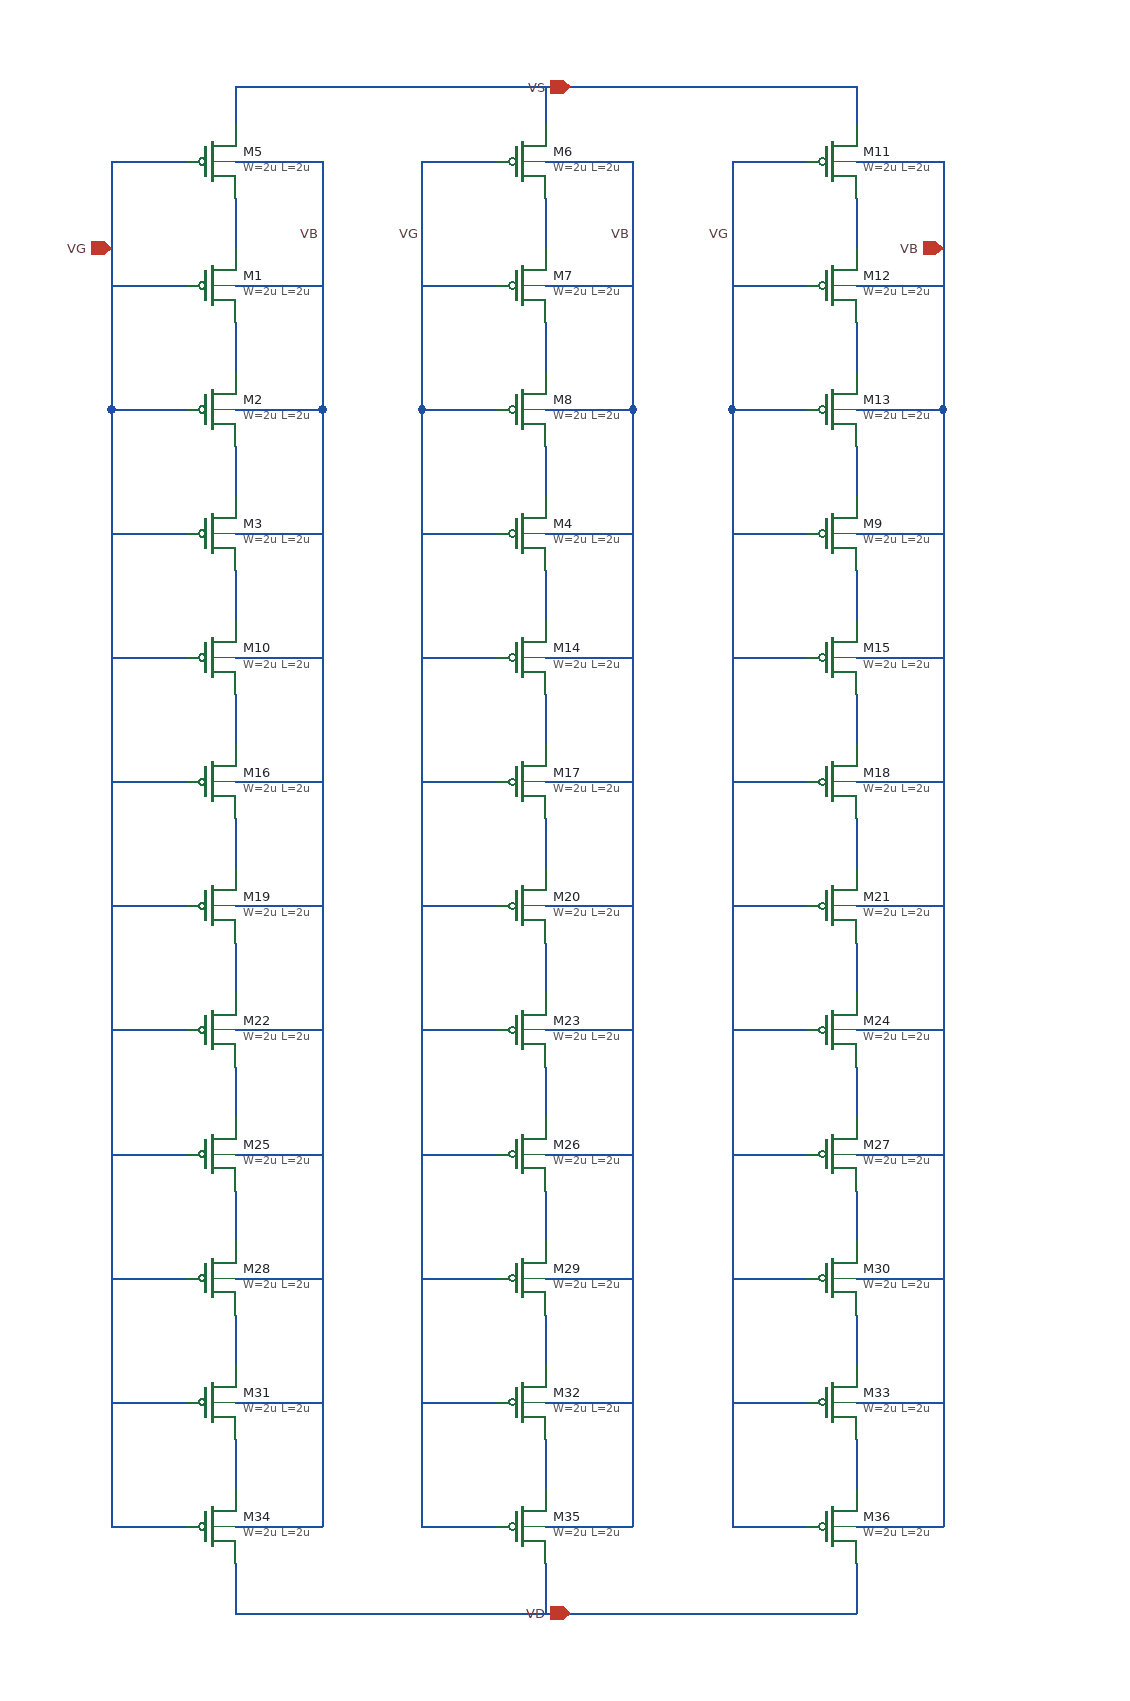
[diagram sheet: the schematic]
v {xschem version=3.4.5 file_version=1.2
}
G {}
K {}
V {}
S {}
E {}
N 10 -60 10 -30 {
lab=VS}
N 10 30 10 70 {
lab=#net1}
N 10 0 80 0 {
lab=VB}
N -90 0 -30 0 {
lab=VG}
N 10 130 10 170 {
lab=#net2}
N 10 1130 10 1170 {
lab=VD}
N -90 200 -30 200 {
lab=VG}
N -90 100 -30 100 {
lab=VG}
N 10 200 80 200 {
lab=VB}
N 10 100 80 100 {
lab=VB}
N 260 -60 260 -30 {
lab=VS}
N 260 30 260 70 {
lab=#net3}
N 260 0 330 0 {
lab=VB}
N 160 0 220 0 {
lab=VG}
N 260 130 260 170 {
lab=#net4}
N 260 1130 260 1170 {
lab=VD}
N 160 200 220 200 {
lab=VG}
N 160 100 220 100 {
lab=VG}
N 260 200 330 200 {
lab=VB}
N 260 100 330 100 {
lab=VB}
N 510 -60 510 -30 {
lab=VS}
N 510 30 510 70 {
lab=#net5}
N 510 0 580 0 {
lab=VB}
N 410 0 470 0 {
lab=#net6}
N 510 130 510 170 {
lab=#net7}
N 510 1130 510 1170 {
lab=VD}
N 410 200 470 200 {
lab=#net6}
N 410 100 470 100 {
lab=#net6}
N 510 200 580 200 {
lab=VB}
N 510 100 580 100 {
lab=VB}
N 10 -60 510 -60 {
lab=VS}
N 10 1170 510 1170 {
lab=VD}
N -90 0 -90 200 {
lab=VG}
N 80 -0 80 200 {
lab=VB}
N 160 -0 160 190 {
lab=VG}
N 160 190 160 200 {
lab=VG}
N 330 0 330 200 {
lab=VB}
N 410 -0 410 200 {
lab=#net6}
N 580 0 580 200 {
lab=VB}
N 10 230 10 270 {
lab=#net2}
N 10 300 80 300 {
lab=VB}
N 260 230 260 270 {
lab=#net4}
N 160 300 220 300 {
lab=VG}
N 260 300 330 300 {
lab=VB}
N 510 230 510 270 {
lab=#net7}
N 410 300 470 300 {
lab=#net6}
N 10 330 10 370 {
lab=#net2}
N 10 400 80 400 {
lab=VB}
N 260 330 260 370 {
lab=#net4}
N 160 400 220 400 {
lab=VG}
N 260 400 330 400 {
lab=VB}
N 510 330 510 370 {
lab=#net7}
N 410 400 470 400 {
lab=#net6}
N 10 430 10 470 {
lab=#net2}
N 10 500 80 500 {
lab=VB}
N 260 430 260 470 {
lab=#net4}
N 160 500 220 500 {
lab=VG}
N 260 500 330 500 {
lab=VB}
N 510 430 510 470 {
lab=#net7}
N 410 500 470 500 {
lab=#net6}
N 10 530 10 570 {
lab=#net2}
N 10 600 80 600 {
lab=VB}
N 260 530 260 570 {
lab=#net4}
N 160 600 220 600 {
lab=VG}
N 260 600 330 600 {
lab=VB}
N 510 530 510 570 {
lab=#net7}
N 410 600 470 600 {
lab=#net6}
N 10 630 10 670 {
lab=#net2}
N 10 700 80 700 {
lab=VB}
N 260 630 260 670 {
lab=#net4}
N 160 700 220 700 {
lab=VG}
N 260 700 330 700 {
lab=VB}
N 510 630 510 670 {
lab=#net7}
N 410 700 470 700 {
lab=#net6}
N 10 730 10 770 {
lab=#net2}
N 10 800 80 800 {
lab=VB}
N 260 730 260 770 {
lab=#net4}
N 160 800 220 800 {
lab=VG}
N 260 800 330 800 {
lab=VB}
N 510 730 510 770 {
lab=#net7}
N 410 800 470 800 {
lab=#net6}
N 10 830 10 870 {
lab=#net2}
N 10 900 80 900 {
lab=VB}
N 260 830 260 870 {
lab=#net4}
N 160 900 220 900 {
lab=VG}
N 260 900 330 900 {
lab=VB}
N 510 830 510 870 {
lab=#net7}
N 410 900 470 900 {
lab=#net6}
N 10 930 10 970 {
lab=#net2}
N 10 1000 80 1000 {
lab=VB}
N 260 930 260 970 {
lab=#net4}
N 160 1000 220 1000 {
lab=VG}
N 260 1000 330 1000 {
lab=VB}
N 510 930 510 970 {
lab=#net7}
N 410 1000 470 1000 {
lab=#net6}
N 10 1030 10 1070 {
lab=#net2}
N 10 1100 80 1100 {
lab=VB}
N 260 1030 260 1070 {
lab=#net4}
N 160 1100 220 1100 {
lab=VG}
N 260 1100 330 1100 {
lab=VB}
N 510 1030 510 1070 {
lab=#net7}
N 410 1100 470 1100 {
lab=#net6}
N 160 1090 160 1100 {
lab=VG}
N 160 200 160 1090 {}
N 330 200 330 1100 {}
N 410 200 410 1100 {}
N 580 200 580 1100 {}
N 510 1100 580 1100 {}
N 510 1000 580 1000 {}
N 510 900 580 900 {}
N 510 800 580 800 {}
N 510 700 570 700 {}
N 570 700 580 700 {}
N 510 600 580 600 {}
N 510 500 580 500 {}
N 510 400 580 400 {}
N 510 300 580 300 {}
N 80 200 80 1100 {}
N -90 200 -90 1100 {}
N -90 1100 -30 1100 {}
N -90 1000 -30 1000 {}
N -90 900 -30 900 {}
N -90 800 -30 800 {}
N -90 700 -30 700 {}
N -90 600 -30 600 {}
N -90 500 -30 500 {}
N -90 400 -30 400 {}
N -90 300 -30 300 {}
C {devices/iopin.sym} 580 70 0 0 {name=p2 lab=VB}
C {devices/iopin.sym} -90 70 2 0 {name=p3 lab=VG}
C {symbols/pfet_03v3.sym} -10 0 0 0 {name=M5
L=2u
W=2u
nf=1
m=1
ad="'int((nf+1)/2) * W/nf * 0.18u'"
pd="'2*int((nf+1)/2) * (W/nf + 0.18u)'"
as="'int((nf+2)/2) * W/nf * 0.18u'"
ps="'2*int((nf+2)/2) * (W/nf + 0.18u)'"
nrd="'0.18u / W'" nrs="'0.18u / W'"
sa=0 sb=0 sd=0
model=pfet_03v3
spiceprefix=X
}
C {devices/iopin.sym} 280 -60 3 0 {name=p4 lab=VS}
C {devices/iopin.sym} 280 1170 1 0 {name=p1 lab=VD}
C {symbols/pfet_03v3.sym} -10 100 0 0 {name=M1
L=2u
W=2u
nf=1
m=1
ad="'int((nf+1)/2) * W/nf * 0.18u'"
pd="'2*int((nf+1)/2) * (W/nf + 0.18u)'"
as="'int((nf+2)/2) * W/nf * 0.18u'"
ps="'2*int((nf+2)/2) * (W/nf + 0.18u)'"
nrd="'0.18u / W'" nrs="'0.18u / W'"
sa=0 sb=0 sd=0
model=pfet_03v3
spiceprefix=X
}
C {symbols/pfet_03v3.sym} -10 200 0 0 {name=M2
L=2u
W=2u
nf=1
m=1
ad="'int((nf+1)/2) * W/nf * 0.18u'"
pd="'2*int((nf+1)/2) * (W/nf + 0.18u)'"
as="'int((nf+2)/2) * W/nf * 0.18u'"
ps="'2*int((nf+2)/2) * (W/nf + 0.18u)'"
nrd="'0.18u / W'" nrs="'0.18u / W'"
sa=0 sb=0 sd=0
model=pfet_03v3
spiceprefix=X
}
C {symbols/pfet_03v3.sym} 240 0 0 0 {name=M6
L=2u
W=2u
nf=1
m=1
ad="'int((nf+1)/2) * W/nf * 0.18u'"
pd="'2*int((nf+1)/2) * (W/nf + 0.18u)'"
as="'int((nf+2)/2) * W/nf * 0.18u'"
ps="'2*int((nf+2)/2) * (W/nf + 0.18u)'"
nrd="'0.18u / W'" nrs="'0.18u / W'"
sa=0 sb=0 sd=0
model=pfet_03v3
spiceprefix=X
}
C {symbols/pfet_03v3.sym} 240 100 0 0 {name=M7
L=2u
W=2u
nf=1
m=1
ad="'int((nf+1)/2) * W/nf * 0.18u'"
pd="'2*int((nf+1)/2) * (W/nf + 0.18u)'"
as="'int((nf+2)/2) * W/nf * 0.18u'"
ps="'2*int((nf+2)/2) * (W/nf + 0.18u)'"
nrd="'0.18u / W'" nrs="'0.18u / W'"
sa=0 sb=0 sd=0
model=pfet_03v3
spiceprefix=X
}
C {symbols/pfet_03v3.sym} 240 200 0 0 {name=M8
L=2u
W=2u
nf=1
m=1
ad="'int((nf+1)/2) * W/nf * 0.18u'"
pd="'2*int((nf+1)/2) * (W/nf + 0.18u)'"
as="'int((nf+2)/2) * W/nf * 0.18u'"
ps="'2*int((nf+2)/2) * (W/nf + 0.18u)'"
nrd="'0.18u / W'" nrs="'0.18u / W'"
sa=0 sb=0 sd=0
model=pfet_03v3
spiceprefix=X
}
C {symbols/pfet_03v3.sym} 490 0 0 0 {name=M11
L=2u
W=2u
nf=1
m=1
ad="'int((nf+1)/2) * W/nf * 0.18u'"
pd="'2*int((nf+1)/2) * (W/nf + 0.18u)'"
as="'int((nf+2)/2) * W/nf * 0.18u'"
ps="'2*int((nf+2)/2) * (W/nf + 0.18u)'"
nrd="'0.18u / W'" nrs="'0.18u / W'"
sa=0 sb=0 sd=0
model=pfet_03v3
spiceprefix=X
}
C {symbols/pfet_03v3.sym} 490 100 0 0 {name=M12
L=2u
W=2u
nf=1
m=1
ad="'int((nf+1)/2) * W/nf * 0.18u'"
pd="'2*int((nf+1)/2) * (W/nf + 0.18u)'"
as="'int((nf+2)/2) * W/nf * 0.18u'"
ps="'2*int((nf+2)/2) * (W/nf + 0.18u)'"
nrd="'0.18u / W'" nrs="'0.18u / W'"
sa=0 sb=0 sd=0
model=pfet_03v3
spiceprefix=X
}
C {symbols/pfet_03v3.sym} 490 200 0 0 {name=M13
L=2u
W=2u
nf=1
m=1
ad="'int((nf+1)/2) * W/nf * 0.18u'"
pd="'2*int((nf+1)/2) * (W/nf + 0.18u)'"
as="'int((nf+2)/2) * W/nf * 0.18u'"
ps="'2*int((nf+2)/2) * (W/nf + 0.18u)'"
nrd="'0.18u / W'" nrs="'0.18u / W'"
sa=0 sb=0 sd=0
model=pfet_03v3
spiceprefix=X
}
C {devices/lab_wire.sym} 80 60 0 0 {name=p9 sig_type=std_logic lab=VB}
C {devices/lab_wire.sym} 330 60 0 0 {name=p5 sig_type=std_logic lab=VB}
C {devices/lab_wire.sym} 160 60 0 0 {name=p6 sig_type=std_logic lab=VG
}
C {devices/lab_wire.sym} 410 60 0 0 {name=p7 sig_type=std_logic lab=VG
}
C {symbols/pfet_03v3.sym} -10 300 0 0 {name=M3
L=2u
W=2u
nf=1
m=1
ad="'int((nf+1)/2) * W/nf * 0.18u'"
pd="'2*int((nf+1)/2) * (W/nf + 0.18u)'"
as="'int((nf+2)/2) * W/nf * 0.18u'"
ps="'2*int((nf+2)/2) * (W/nf + 0.18u)'"
nrd="'0.18u / W'" nrs="'0.18u / W'"
sa=0 sb=0 sd=0
model=pfet_03v3
spiceprefix=X
}
C {symbols/pfet_03v3.sym} 240 300 0 0 {name=M4
L=2u
W=2u
nf=1
m=1
ad="'int((nf+1)/2) * W/nf * 0.18u'"
pd="'2*int((nf+1)/2) * (W/nf + 0.18u)'"
as="'int((nf+2)/2) * W/nf * 0.18u'"
ps="'2*int((nf+2)/2) * (W/nf + 0.18u)'"
nrd="'0.18u / W'" nrs="'0.18u / W'"
sa=0 sb=0 sd=0
model=pfet_03v3
spiceprefix=X
}
C {symbols/pfet_03v3.sym} 490 300 0 0 {name=M9
L=2u
W=2u
nf=1
m=1
ad="'int((nf+1)/2) * W/nf * 0.18u'"
pd="'2*int((nf+1)/2) * (W/nf + 0.18u)'"
as="'int((nf+2)/2) * W/nf * 0.18u'"
ps="'2*int((nf+2)/2) * (W/nf + 0.18u)'"
nrd="'0.18u / W'" nrs="'0.18u / W'"
sa=0 sb=0 sd=0
model=pfet_03v3
spiceprefix=X
}
C {symbols/pfet_03v3.sym} -10 400 0 0 {name=M10
L=2u
W=2u
nf=1
m=1
ad="'int((nf+1)/2) * W/nf * 0.18u'"
pd="'2*int((nf+1)/2) * (W/nf + 0.18u)'"
as="'int((nf+2)/2) * W/nf * 0.18u'"
ps="'2*int((nf+2)/2) * (W/nf + 0.18u)'"
nrd="'0.18u / W'" nrs="'0.18u / W'"
sa=0 sb=0 sd=0
model=pfet_03v3
spiceprefix=X
}
C {symbols/pfet_03v3.sym} 240 400 0 0 {name=M14
L=2u
W=2u
nf=1
m=1
ad="'int((nf+1)/2) * W/nf * 0.18u'"
pd="'2*int((nf+1)/2) * (W/nf + 0.18u)'"
as="'int((nf+2)/2) * W/nf * 0.18u'"
ps="'2*int((nf+2)/2) * (W/nf + 0.18u)'"
nrd="'0.18u / W'" nrs="'0.18u / W'"
sa=0 sb=0 sd=0
model=pfet_03v3
spiceprefix=X
}
C {symbols/pfet_03v3.sym} 490 400 0 0 {name=M15
L=2u
W=2u
nf=1
m=1
ad="'int((nf+1)/2) * W/nf * 0.18u'"
pd="'2*int((nf+1)/2) * (W/nf + 0.18u)'"
as="'int((nf+2)/2) * W/nf * 0.18u'"
ps="'2*int((nf+2)/2) * (W/nf + 0.18u)'"
nrd="'0.18u / W'" nrs="'0.18u / W'"
sa=0 sb=0 sd=0
model=pfet_03v3
spiceprefix=X
}
C {symbols/pfet_03v3.sym} -10 500 0 0 {name=M16
L=2u
W=2u
nf=1
m=1
ad="'int((nf+1)/2) * W/nf * 0.18u'"
pd="'2*int((nf+1)/2) * (W/nf + 0.18u)'"
as="'int((nf+2)/2) * W/nf * 0.18u'"
ps="'2*int((nf+2)/2) * (W/nf + 0.18u)'"
nrd="'0.18u / W'" nrs="'0.18u / W'"
sa=0 sb=0 sd=0
model=pfet_03v3
spiceprefix=X
}
C {symbols/pfet_03v3.sym} 240 500 0 0 {name=M17
L=2u
W=2u
nf=1
m=1
ad="'int((nf+1)/2) * W/nf * 0.18u'"
pd="'2*int((nf+1)/2) * (W/nf + 0.18u)'"
as="'int((nf+2)/2) * W/nf * 0.18u'"
ps="'2*int((nf+2)/2) * (W/nf + 0.18u)'"
nrd="'0.18u / W'" nrs="'0.18u / W'"
sa=0 sb=0 sd=0
model=pfet_03v3
spiceprefix=X
}
C {symbols/pfet_03v3.sym} 490 500 0 0 {name=M18
L=2u
W=2u
nf=1
m=1
ad="'int((nf+1)/2) * W/nf * 0.18u'"
pd="'2*int((nf+1)/2) * (W/nf + 0.18u)'"
as="'int((nf+2)/2) * W/nf * 0.18u'"
ps="'2*int((nf+2)/2) * (W/nf + 0.18u)'"
nrd="'0.18u / W'" nrs="'0.18u / W'"
sa=0 sb=0 sd=0
model=pfet_03v3
spiceprefix=X
}
C {symbols/pfet_03v3.sym} -10 600 0 0 {name=M19
L=2u
W=2u
nf=1
m=1
ad="'int((nf+1)/2) * W/nf * 0.18u'"
pd="'2*int((nf+1)/2) * (W/nf + 0.18u)'"
as="'int((nf+2)/2) * W/nf * 0.18u'"
ps="'2*int((nf+2)/2) * (W/nf + 0.18u)'"
nrd="'0.18u / W'" nrs="'0.18u / W'"
sa=0 sb=0 sd=0
model=pfet_03v3
spiceprefix=X
}
C {symbols/pfet_03v3.sym} 240 600 0 0 {name=M20
L=2u
W=2u
nf=1
m=1
ad="'int((nf+1)/2) * W/nf * 0.18u'"
pd="'2*int((nf+1)/2) * (W/nf + 0.18u)'"
as="'int((nf+2)/2) * W/nf * 0.18u'"
ps="'2*int((nf+2)/2) * (W/nf + 0.18u)'"
nrd="'0.18u / W'" nrs="'0.18u / W'"
sa=0 sb=0 sd=0
model=pfet_03v3
spiceprefix=X
}
C {symbols/pfet_03v3.sym} 490 600 0 0 {name=M21
L=2u
W=2u
nf=1
m=1
ad="'int((nf+1)/2) * W/nf * 0.18u'"
pd="'2*int((nf+1)/2) * (W/nf + 0.18u)'"
as="'int((nf+2)/2) * W/nf * 0.18u'"
ps="'2*int((nf+2)/2) * (W/nf + 0.18u)'"
nrd="'0.18u / W'" nrs="'0.18u / W'"
sa=0 sb=0 sd=0
model=pfet_03v3
spiceprefix=X
}
C {symbols/pfet_03v3.sym} -10 700 0 0 {name=M22
L=2u
W=2u
nf=1
m=1
ad="'int((nf+1)/2) * W/nf * 0.18u'"
pd="'2*int((nf+1)/2) * (W/nf + 0.18u)'"
as="'int((nf+2)/2) * W/nf * 0.18u'"
ps="'2*int((nf+2)/2) * (W/nf + 0.18u)'"
nrd="'0.18u / W'" nrs="'0.18u / W'"
sa=0 sb=0 sd=0
model=pfet_03v3
spiceprefix=X
}
C {symbols/pfet_03v3.sym} 240 700 0 0 {name=M23
L=2u
W=2u
nf=1
m=1
ad="'int((nf+1)/2) * W/nf * 0.18u'"
pd="'2*int((nf+1)/2) * (W/nf + 0.18u)'"
as="'int((nf+2)/2) * W/nf * 0.18u'"
ps="'2*int((nf+2)/2) * (W/nf + 0.18u)'"
nrd="'0.18u / W'" nrs="'0.18u / W'"
sa=0 sb=0 sd=0
model=pfet_03v3
spiceprefix=X
}
C {symbols/pfet_03v3.sym} 490 700 0 0 {name=M24
L=2u
W=2u
nf=1
m=1
ad="'int((nf+1)/2) * W/nf * 0.18u'"
pd="'2*int((nf+1)/2) * (W/nf + 0.18u)'"
as="'int((nf+2)/2) * W/nf * 0.18u'"
ps="'2*int((nf+2)/2) * (W/nf + 0.18u)'"
nrd="'0.18u / W'" nrs="'0.18u / W'"
sa=0 sb=0 sd=0
model=pfet_03v3
spiceprefix=X
}
C {symbols/pfet_03v3.sym} -10 800 0 0 {name=M25
L=2u
W=2u
nf=1
m=1
ad="'int((nf+1)/2) * W/nf * 0.18u'"
pd="'2*int((nf+1)/2) * (W/nf + 0.18u)'"
as="'int((nf+2)/2) * W/nf * 0.18u'"
ps="'2*int((nf+2)/2) * (W/nf + 0.18u)'"
nrd="'0.18u / W'" nrs="'0.18u / W'"
sa=0 sb=0 sd=0
model=pfet_03v3
spiceprefix=X
}
C {symbols/pfet_03v3.sym} 240 800 0 0 {name=M26
L=2u
W=2u
nf=1
m=1
ad="'int((nf+1)/2) * W/nf * 0.18u'"
pd="'2*int((nf+1)/2) * (W/nf + 0.18u)'"
as="'int((nf+2)/2) * W/nf * 0.18u'"
ps="'2*int((nf+2)/2) * (W/nf + 0.18u)'"
nrd="'0.18u / W'" nrs="'0.18u / W'"
sa=0 sb=0 sd=0
model=pfet_03v3
spiceprefix=X
}
C {symbols/pfet_03v3.sym} 490 800 0 0 {name=M27
L=2u
W=2u
nf=1
m=1
ad="'int((nf+1)/2) * W/nf * 0.18u'"
pd="'2*int((nf+1)/2) * (W/nf + 0.18u)'"
as="'int((nf+2)/2) * W/nf * 0.18u'"
ps="'2*int((nf+2)/2) * (W/nf + 0.18u)'"
nrd="'0.18u / W'" nrs="'0.18u / W'"
sa=0 sb=0 sd=0
model=pfet_03v3
spiceprefix=X
}
C {symbols/pfet_03v3.sym} -10 900 0 0 {name=M28
L=2u
W=2u
nf=1
m=1
ad="'int((nf+1)/2) * W/nf * 0.18u'"
pd="'2*int((nf+1)/2) * (W/nf + 0.18u)'"
as="'int((nf+2)/2) * W/nf * 0.18u'"
ps="'2*int((nf+2)/2) * (W/nf + 0.18u)'"
nrd="'0.18u / W'" nrs="'0.18u / W'"
sa=0 sb=0 sd=0
model=pfet_03v3
spiceprefix=X
}
C {symbols/pfet_03v3.sym} 240 900 0 0 {name=M29
L=2u
W=2u
nf=1
m=1
ad="'int((nf+1)/2) * W/nf * 0.18u'"
pd="'2*int((nf+1)/2) * (W/nf + 0.18u)'"
as="'int((nf+2)/2) * W/nf * 0.18u'"
ps="'2*int((nf+2)/2) * (W/nf + 0.18u)'"
nrd="'0.18u / W'" nrs="'0.18u / W'"
sa=0 sb=0 sd=0
model=pfet_03v3
spiceprefix=X
}
C {symbols/pfet_03v3.sym} 490 900 0 0 {name=M30
L=2u
W=2u
nf=1
m=1
ad="'int((nf+1)/2) * W/nf * 0.18u'"
pd="'2*int((nf+1)/2) * (W/nf + 0.18u)'"
as="'int((nf+2)/2) * W/nf * 0.18u'"
ps="'2*int((nf+2)/2) * (W/nf + 0.18u)'"
nrd="'0.18u / W'" nrs="'0.18u / W'"
sa=0 sb=0 sd=0
model=pfet_03v3
spiceprefix=X
}
C {symbols/pfet_03v3.sym} -10 1000 0 0 {name=M31
L=2u
W=2u
nf=1
m=1
ad="'int((nf+1)/2) * W/nf * 0.18u'"
pd="'2*int((nf+1)/2) * (W/nf + 0.18u)'"
as="'int((nf+2)/2) * W/nf * 0.18u'"
ps="'2*int((nf+2)/2) * (W/nf + 0.18u)'"
nrd="'0.18u / W'" nrs="'0.18u / W'"
sa=0 sb=0 sd=0
model=pfet_03v3
spiceprefix=X
}
C {symbols/pfet_03v3.sym} 240 1000 0 0 {name=M32
L=2u
W=2u
nf=1
m=1
ad="'int((nf+1)/2) * W/nf * 0.18u'"
pd="'2*int((nf+1)/2) * (W/nf + 0.18u)'"
as="'int((nf+2)/2) * W/nf * 0.18u'"
ps="'2*int((nf+2)/2) * (W/nf + 0.18u)'"
nrd="'0.18u / W'" nrs="'0.18u / W'"
sa=0 sb=0 sd=0
model=pfet_03v3
spiceprefix=X
}
C {symbols/pfet_03v3.sym} 490 1000 0 0 {name=M33
L=2u
W=2u
nf=1
m=1
ad="'int((nf+1)/2) * W/nf * 0.18u'"
pd="'2*int((nf+1)/2) * (W/nf + 0.18u)'"
as="'int((nf+2)/2) * W/nf * 0.18u'"
ps="'2*int((nf+2)/2) * (W/nf + 0.18u)'"
nrd="'0.18u / W'" nrs="'0.18u / W'"
sa=0 sb=0 sd=0
model=pfet_03v3
spiceprefix=X
}
C {symbols/pfet_03v3.sym} -10 1100 0 0 {name=M34
L=2u
W=2u
nf=1
m=1
ad="'int((nf+1)/2) * W/nf * 0.18u'"
pd="'2*int((nf+1)/2) * (W/nf + 0.18u)'"
as="'int((nf+2)/2) * W/nf * 0.18u'"
ps="'2*int((nf+2)/2) * (W/nf + 0.18u)'"
nrd="'0.18u / W'" nrs="'0.18u / W'"
sa=0 sb=0 sd=0
model=pfet_03v3
spiceprefix=X
}
C {symbols/pfet_03v3.sym} 240 1100 0 0 {name=M35
L=2u
W=2u
nf=1
m=1
ad="'int((nf+1)/2) * W/nf * 0.18u'"
pd="'2*int((nf+1)/2) * (W/nf + 0.18u)'"
as="'int((nf+2)/2) * W/nf * 0.18u'"
ps="'2*int((nf+2)/2) * (W/nf + 0.18u)'"
nrd="'0.18u / W'" nrs="'0.18u / W'"
sa=0 sb=0 sd=0
model=pfet_03v3
spiceprefix=X
}
C {symbols/pfet_03v3.sym} 490 1100 0 0 {name=M36
L=2u
W=2u
nf=1
m=1
ad="'int((nf+1)/2) * W/nf * 0.18u'"
pd="'2*int((nf+1)/2) * (W/nf + 0.18u)'"
as="'int((nf+2)/2) * W/nf * 0.18u'"
ps="'2*int((nf+2)/2) * (W/nf + 0.18u)'"
nrd="'0.18u / W'" nrs="'0.18u / W'"
sa=0 sb=0 sd=0
model=pfet_03v3
spiceprefix=X
}
